VERSION 5.7 ;
  NOWIREEXTENSIONATPIN ON ;
  DIVIDERCHAR "/" ;
  BUSBITCHARS "[]" ;
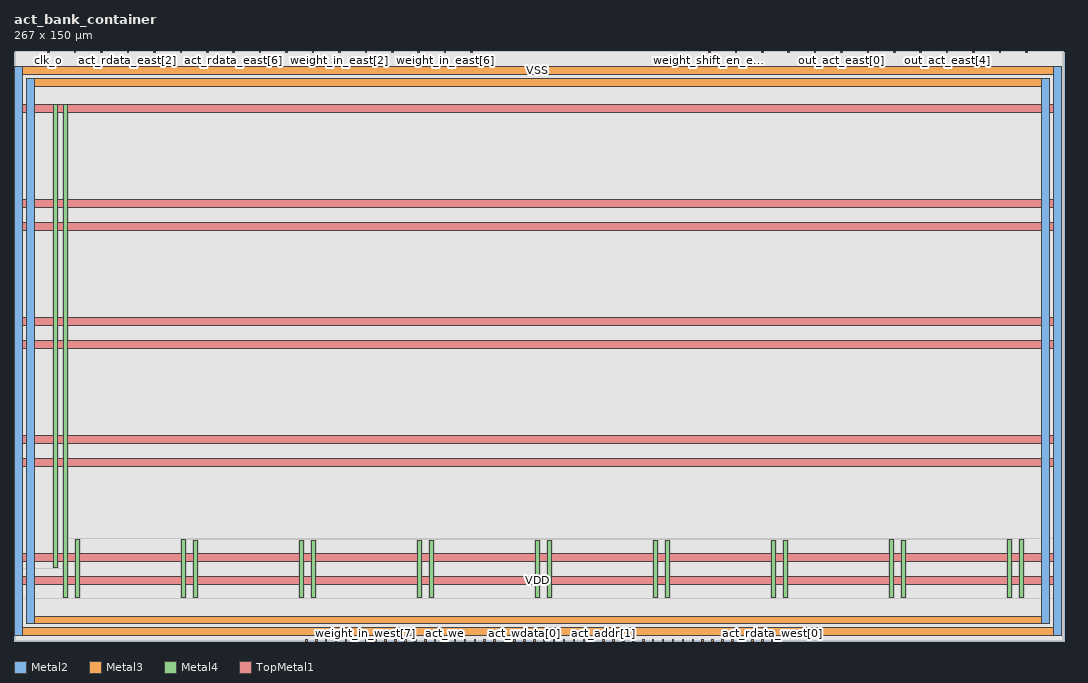
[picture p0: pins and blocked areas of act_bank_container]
MACRO act_bank_container
  CLASS BLOCK ;
  FOREIGN act_bank_container ;
  ORIGIN 0.000 0.000 ;
  SIZE 267.000 BY 150.000 ;
  PIN VDD
    DIRECTION INOUT ;
    USE POWER ;
    PORT
      LAYER Metal2 ;
        RECT 3.120 4.340 5.120 143.080 ;
    END
    PORT
      LAYER Metal2 ;
        RECT 261.280 4.340 263.280 143.080 ;
    END
    PORT
      LAYER Metal3 ;
        RECT 3.120 4.340 263.280 6.340 ;
    END
    PORT
      LAYER Metal3 ;
        RECT 3.120 141.080 263.280 143.080 ;
    END
    PORT
      LAYER Metal4 ;
        RECT 12.620 11.120 13.620 136.340 ;
    END
    PORT
      LAYER Metal4 ;
        RECT 42.620 11.120 43.620 25.760 ;
    END
    PORT
      LAYER Metal4 ;
        RECT 72.620 11.120 73.620 25.520 ;
    END
    PORT
      LAYER Metal4 ;
        RECT 102.620 11.120 103.620 25.520 ;
    END
    PORT
      LAYER Metal4 ;
        RECT 132.620 11.120 133.620 25.520 ;
    END
    PORT
      LAYER Metal4 ;
        RECT 162.620 11.120 163.620 25.520 ;
    END
    PORT
      LAYER Metal4 ;
        RECT 192.620 11.120 193.620 25.520 ;
    END
    PORT
      LAYER Metal4 ;
        RECT 222.620 11.120 223.620 25.760 ;
    END
    PORT
      LAYER Metal4 ;
        RECT 252.620 11.120 253.620 25.760 ;
    END
    PORT
      LAYER TopMetal1 ;
        RECT 0.120 14.340 266.280 16.340 ;
    END
    PORT
      LAYER TopMetal1 ;
        RECT 0.120 44.340 266.280 46.340 ;
    END
    PORT
      LAYER TopMetal1 ;
        RECT 0.120 74.340 266.280 76.340 ;
    END
    PORT
      LAYER TopMetal1 ;
        RECT 0.120 104.340 266.280 106.340 ;
    END
    PORT
      LAYER TopMetal1 ;
        RECT 0.120 134.340 266.280 136.340 ;
    END
  END VDD
  PIN VSS
    DIRECTION INOUT ;
    USE GROUND ;
    PORT
      LAYER Metal2 ;
        RECT 0.120 1.340 2.120 146.080 ;
    END
    PORT
      LAYER Metal2 ;
        RECT 264.280 1.340 266.280 146.080 ;
    END
    PORT
      LAYER Metal3 ;
        RECT 0.120 1.340 266.280 3.340 ;
    END
    PORT
      LAYER Metal3 ;
        RECT 0.120 144.080 266.280 146.080 ;
    END
    PORT
      LAYER Metal4 ;
        RECT 15.620 11.120 16.620 25.760 ;
    END
    PORT
      LAYER Metal4 ;
        RECT 45.620 11.120 46.620 25.520 ;
    END
    PORT
      LAYER Metal4 ;
        RECT 75.620 11.120 76.620 25.520 ;
    END
    PORT
      LAYER Metal4 ;
        RECT 105.620 11.120 106.620 25.520 ;
    END
    PORT
      LAYER Metal4 ;
        RECT 135.620 11.120 136.620 25.520 ;
    END
    PORT
      LAYER Metal4 ;
        RECT 165.620 11.120 166.620 25.520 ;
    END
    PORT
      LAYER Metal4 ;
        RECT 195.620 11.120 196.620 25.520 ;
    END
    PORT
      LAYER Metal4 ;
        RECT 225.620 11.120 226.620 25.520 ;
    END
    PORT
      LAYER Metal4 ;
        RECT 255.620 11.120 256.620 25.760 ;
    END
    PORT
      LAYER TopMetal1 ;
        RECT 0.120 20.340 266.280 22.340 ;
    END
    PORT
      LAYER TopMetal1 ;
        RECT 0.120 50.340 266.280 52.340 ;
    END
    PORT
      LAYER TopMetal1 ;
        RECT 0.120 80.340 266.280 82.340 ;
    END
    PORT
      LAYER TopMetal1 ;
        RECT 0.120 110.340 266.280 112.340 ;
    END
    PORT
      LAYER Metal4 ;
        RECT 10.060 18.680 11.060 136.300 ;
    END
  END VSS
  PIN act_addr[0]
    DIRECTION INPUT ;
    USE SIGNAL ;
    ANTENNAGATEAREA 0.180700 ;
    PORT
      LAYER Metal3 ;
        RECT 152.260 0.000 152.660 0.400 ;
    END
  END act_addr[0]
  PIN act_addr[1]
    DIRECTION INPUT ;
    USE SIGNAL ;
    ANTENNAGATEAREA 0.180700 ;
    PORT
      LAYER Metal3 ;
        RECT 149.740 0.000 150.140 0.400 ;
    END
  END act_addr[1]
  PIN act_addr[2]
    DIRECTION INPUT ;
    USE SIGNAL ;
    ANTENNAGATEAREA 0.180700 ;
    PORT
      LAYER Metal3 ;
        RECT 147.220 0.000 147.620 0.400 ;
    END
  END act_addr[2]
  PIN act_addr[3]
    DIRECTION INPUT ;
    USE SIGNAL ;
    ANTENNAGATEAREA 0.180700 ;
    PORT
      LAYER Metal3 ;
        RECT 144.700 0.000 145.100 0.400 ;
    END
  END act_addr[3]
  PIN act_addr[4]
    DIRECTION INPUT ;
    USE SIGNAL ;
    ANTENNAGATEAREA 0.180700 ;
    PORT
      LAYER Metal3 ;
        RECT 142.180 0.000 142.580 0.400 ;
    END
  END act_addr[4]
  PIN act_addr[5]
    DIRECTION INPUT ;
    USE SIGNAL ;
    ANTENNAGATEAREA 0.180700 ;
    PORT
      LAYER Metal3 ;
        RECT 139.660 0.000 140.060 0.400 ;
    END
  END act_addr[5]
  PIN act_addr[6]
    DIRECTION INPUT ;
    USE SIGNAL ;
    ANTENNAGATEAREA 0.180700 ;
    PORT
      LAYER Metal3 ;
        RECT 137.140 0.000 137.540 0.400 ;
    END
  END act_addr[6]
  PIN act_addr[7]
    DIRECTION INPUT ;
    USE SIGNAL ;
    ANTENNAGATEAREA 0.180700 ;
    PORT
      LAYER Metal3 ;
        RECT 134.620 0.000 135.020 0.400 ;
    END
  END act_addr[7]
  PIN act_addr[8]
    DIRECTION INPUT ;
    USE SIGNAL ;
    ANTENNAGATEAREA 0.180700 ;
    PORT
      LAYER Metal3 ;
        RECT 132.100 0.000 132.500 0.400 ;
    END
  END act_addr[8]
  PIN act_rdata_east[0]
    DIRECTION OUTPUT ;
    USE SIGNAL ;
    ANTENNADIFFAREA 0.708600 ;
    PORT
      LAYER Metal3 ;
        RECT 15.340 149.600 15.740 150.000 ;
    END
  END act_rdata_east[0]
  PIN act_rdata_east[1]
    DIRECTION OUTPUT ;
    USE SIGNAL ;
    ANTENNADIFFAREA 0.708600 ;
    PORT
      LAYER Metal3 ;
        RECT 22.060 149.600 22.460 150.000 ;
    END
  END act_rdata_east[1]
  PIN act_rdata_east[2]
    DIRECTION OUTPUT ;
    USE SIGNAL ;
    ANTENNADIFFAREA 0.708600 ;
    PORT
      LAYER Metal3 ;
        RECT 28.780 149.600 29.180 150.000 ;
    END
  END act_rdata_east[2]
  PIN act_rdata_east[3]
    DIRECTION OUTPUT ;
    USE SIGNAL ;
    ANTENNADIFFAREA 0.708600 ;
    PORT
      LAYER Metal3 ;
        RECT 35.500 149.600 35.900 150.000 ;
    END
  END act_rdata_east[3]
  PIN act_rdata_east[4]
    DIRECTION OUTPUT ;
    USE SIGNAL ;
    ANTENNADIFFAREA 0.708600 ;
    PORT
      LAYER Metal3 ;
        RECT 42.220 149.600 42.620 150.000 ;
    END
  END act_rdata_east[4]
  PIN act_rdata_east[5]
    DIRECTION OUTPUT ;
    USE SIGNAL ;
    ANTENNADIFFAREA 0.708600 ;
    PORT
      LAYER Metal3 ;
        RECT 48.940 149.600 49.340 150.000 ;
    END
  END act_rdata_east[5]
  PIN act_rdata_east[6]
    DIRECTION OUTPUT ;
    USE SIGNAL ;
    ANTENNADIFFAREA 0.708600 ;
    PORT
      LAYER Metal3 ;
        RECT 55.660 149.600 56.060 150.000 ;
    END
  END act_rdata_east[6]
  PIN act_rdata_east[7]
    DIRECTION OUTPUT ;
    USE SIGNAL ;
    ANTENNADIFFAREA 0.708600 ;
    PORT
      LAYER Metal3 ;
        RECT 62.380 149.600 62.780 150.000 ;
    END
  END act_rdata_east[7]
  PIN act_rdata_west[0]
    DIRECTION OUTPUT ;
    USE SIGNAL ;
    ANTENNADIFFAREA 0.708600 ;
    PORT
      LAYER Metal3 ;
        RECT 192.580 0.000 192.980 0.400 ;
    END
  END act_rdata_west[0]
  PIN act_rdata_west[1]
    DIRECTION OUTPUT ;
    USE SIGNAL ;
    ANTENNADIFFAREA 0.708600 ;
    PORT
      LAYER Metal3 ;
        RECT 190.060 0.000 190.460 0.400 ;
    END
  END act_rdata_west[1]
  PIN act_rdata_west[2]
    DIRECTION OUTPUT ;
    USE SIGNAL ;
    ANTENNADIFFAREA 0.708600 ;
    PORT
      LAYER Metal3 ;
        RECT 187.540 0.000 187.940 0.400 ;
    END
  END act_rdata_west[2]
  PIN act_rdata_west[3]
    DIRECTION OUTPUT ;
    USE SIGNAL ;
    ANTENNADIFFAREA 0.708600 ;
    PORT
      LAYER Metal3 ;
        RECT 185.020 0.000 185.420 0.400 ;
    END
  END act_rdata_west[3]
  PIN act_rdata_west[4]
    DIRECTION OUTPUT ;
    USE SIGNAL ;
    ANTENNADIFFAREA 0.708600 ;
    PORT
      LAYER Metal3 ;
        RECT 182.500 0.000 182.900 0.400 ;
    END
  END act_rdata_west[4]
  PIN act_rdata_west[5]
    DIRECTION OUTPUT ;
    USE SIGNAL ;
    ANTENNADIFFAREA 0.708600 ;
    PORT
      LAYER Metal3 ;
        RECT 179.980 0.000 180.380 0.400 ;
    END
  END act_rdata_west[5]
  PIN act_rdata_west[6]
    DIRECTION OUTPUT ;
    USE SIGNAL ;
    ANTENNADIFFAREA 0.708600 ;
    PORT
      LAYER Metal3 ;
        RECT 177.460 0.000 177.860 0.400 ;
    END
  END act_rdata_west[6]
  PIN act_rdata_west[7]
    DIRECTION OUTPUT ;
    USE SIGNAL ;
    ANTENNADIFFAREA 0.708600 ;
    PORT
      LAYER Metal3 ;
        RECT 174.940 0.000 175.340 0.400 ;
    END
  END act_rdata_west[7]
  PIN act_wdata[0]
    DIRECTION INPUT ;
    USE SIGNAL ;
    ANTENNAGATEAREA 0.180700 ;
    PORT
      LAYER Metal3 ;
        RECT 129.580 0.000 129.980 0.400 ;
    END
  END act_wdata[0]
  PIN act_wdata[1]
    DIRECTION INPUT ;
    USE SIGNAL ;
    ANTENNAGATEAREA 0.180700 ;
    PORT
      LAYER Metal3 ;
        RECT 127.060 0.000 127.460 0.400 ;
    END
  END act_wdata[1]
  PIN act_wdata[2]
    DIRECTION INPUT ;
    USE SIGNAL ;
    ANTENNAGATEAREA 0.180700 ;
    PORT
      LAYER Metal3 ;
        RECT 124.540 0.000 124.940 0.400 ;
    END
  END act_wdata[2]
  PIN act_wdata[3]
    DIRECTION INPUT ;
    USE SIGNAL ;
    ANTENNAGATEAREA 0.180700 ;
    PORT
      LAYER Metal3 ;
        RECT 122.020 0.000 122.420 0.400 ;
    END
  END act_wdata[3]
  PIN act_wdata[4]
    DIRECTION INPUT ;
    USE SIGNAL ;
    ANTENNAGATEAREA 0.180700 ;
    PORT
      LAYER Metal3 ;
        RECT 119.500 0.000 119.900 0.400 ;
    END
  END act_wdata[4]
  PIN act_wdata[5]
    DIRECTION INPUT ;
    USE SIGNAL ;
    ANTENNAGATEAREA 0.180700 ;
    PORT
      LAYER Metal3 ;
        RECT 116.980 0.000 117.380 0.400 ;
    END
  END act_wdata[5]
  PIN act_wdata[6]
    DIRECTION INPUT ;
    USE SIGNAL ;
    ANTENNAGATEAREA 0.180700 ;
    PORT
      LAYER Metal3 ;
        RECT 114.460 0.000 114.860 0.400 ;
    END
  END act_wdata[6]
  PIN act_wdata[7]
    DIRECTION INPUT ;
    USE SIGNAL ;
    ANTENNAGATEAREA 0.180700 ;
    PORT
      LAYER Metal3 ;
        RECT 111.940 0.000 112.340 0.400 ;
    END
  END act_wdata[7]
  PIN act_we
    DIRECTION INPUT ;
    USE SIGNAL ;
    ANTENNAGATEAREA 0.180700 ;
    PORT
      LAYER Metal3 ;
        RECT 109.420 0.000 109.820 0.400 ;
    END
  END act_we
  PIN clk_i
    DIRECTION INPUT ;
    USE SIGNAL ;
    ANTENNAGATEAREA 0.381550 ;
    PORT
      LAYER Metal3 ;
        RECT 74.140 0.000 74.540 0.400 ;
    END
  END clk_i
  PIN clk_o
    DIRECTION OUTPUT ;
    USE SIGNAL ;
    ANTENNADIFFAREA 0.708600 ;
    PORT
      LAYER Metal3 ;
        RECT 8.620 149.600 9.020 150.000 ;
    END
  END clk_o
  PIN out_act_east[0]
    DIRECTION INPUT ;
    USE SIGNAL ;
    ANTENNAGATEAREA 0.180700 ;
    PORT
      LAYER Metal3 ;
        RECT 210.220 149.600 210.620 150.000 ;
    END
  END out_act_east[0]
  PIN out_act_east[1]
    DIRECTION INPUT ;
    USE SIGNAL ;
    ANTENNAGATEAREA 0.180700 ;
    PORT
      LAYER Metal3 ;
        RECT 216.940 149.600 217.340 150.000 ;
    END
  END out_act_east[1]
  PIN out_act_east[2]
    DIRECTION INPUT ;
    USE SIGNAL ;
    ANTENNAGATEAREA 0.180700 ;
    ANTENNADIFFAREA 2.015400 ;
    PORT
      LAYER Metal3 ;
        RECT 223.660 149.600 224.060 150.000 ;
    END
  END out_act_east[2]
  PIN out_act_east[3]
    DIRECTION INPUT ;
    USE SIGNAL ;
    ANTENNAGATEAREA 0.180700 ;
    ANTENNADIFFAREA 2.015400 ;
    PORT
      LAYER Metal3 ;
        RECT 230.380 149.600 230.780 150.000 ;
    END
  END out_act_east[3]
  PIN out_act_east[4]
    DIRECTION INPUT ;
    USE SIGNAL ;
    ANTENNAGATEAREA 0.180700 ;
    PORT
      LAYER Metal3 ;
        RECT 237.100 149.600 237.500 150.000 ;
    END
  END out_act_east[4]
  PIN out_act_east[5]
    DIRECTION INPUT ;
    USE SIGNAL ;
    ANTENNAGATEAREA 0.180700 ;
    PORT
      LAYER Metal3 ;
        RECT 243.820 149.600 244.220 150.000 ;
    END
  END out_act_east[5]
  PIN out_act_east[6]
    DIRECTION INPUT ;
    USE SIGNAL ;
    ANTENNAGATEAREA 0.180700 ;
    PORT
      LAYER Metal3 ;
        RECT 250.540 149.600 250.940 150.000 ;
    END
  END out_act_east[6]
  PIN out_act_east[7]
    DIRECTION INPUT ;
    USE SIGNAL ;
    ANTENNAGATEAREA 0.180700 ;
    PORT
      LAYER Metal3 ;
        RECT 257.260 149.600 257.660 150.000 ;
    END
  END out_act_east[7]
  PIN out_act_west[0]
    DIRECTION OUTPUT ;
    USE SIGNAL ;
    ANTENNADIFFAREA 0.708600 ;
    PORT
      LAYER Metal3 ;
        RECT 172.420 0.000 172.820 0.400 ;
    END
  END out_act_west[0]
  PIN out_act_west[1]
    DIRECTION OUTPUT ;
    USE SIGNAL ;
    ANTENNADIFFAREA 0.708600 ;
    PORT
      LAYER Metal3 ;
        RECT 169.900 0.000 170.300 0.400 ;
    END
  END out_act_west[1]
  PIN out_act_west[2]
    DIRECTION OUTPUT ;
    USE SIGNAL ;
    ANTENNADIFFAREA 0.708600 ;
    PORT
      LAYER Metal3 ;
        RECT 167.380 0.000 167.780 0.400 ;
    END
  END out_act_west[2]
  PIN out_act_west[3]
    DIRECTION OUTPUT ;
    USE SIGNAL ;
    ANTENNADIFFAREA 0.708600 ;
    PORT
      LAYER Metal3 ;
        RECT 164.860 0.000 165.260 0.400 ;
    END
  END out_act_west[3]
  PIN out_act_west[4]
    DIRECTION OUTPUT ;
    USE SIGNAL ;
    ANTENNADIFFAREA 0.708600 ;
    PORT
      LAYER Metal3 ;
        RECT 162.340 0.000 162.740 0.400 ;
    END
  END out_act_west[4]
  PIN out_act_west[5]
    DIRECTION OUTPUT ;
    USE SIGNAL ;
    ANTENNADIFFAREA 0.708600 ;
    PORT
      LAYER Metal3 ;
        RECT 159.820 0.000 160.220 0.400 ;
    END
  END out_act_west[5]
  PIN out_act_west[6]
    DIRECTION OUTPUT ;
    USE SIGNAL ;
    ANTENNADIFFAREA 0.708600 ;
    PORT
      LAYER Metal3 ;
        RECT 157.300 0.000 157.700 0.400 ;
    END
  END out_act_west[6]
  PIN out_act_west[7]
    DIRECTION OUTPUT ;
    USE SIGNAL ;
    ANTENNADIFFAREA 0.708600 ;
    PORT
      LAYER Metal3 ;
        RECT 154.780 0.000 155.180 0.400 ;
    END
  END out_act_west[7]
  PIN weight_in_east[0]
    DIRECTION OUTPUT ;
    USE SIGNAL ;
    ANTENNADIFFAREA 0.708600 ;
    PORT
      LAYER Metal3 ;
        RECT 69.100 149.600 69.500 150.000 ;
    END
  END weight_in_east[0]
  PIN weight_in_east[1]
    DIRECTION OUTPUT ;
    USE SIGNAL ;
    ANTENNADIFFAREA 0.708600 ;
    PORT
      LAYER Metal3 ;
        RECT 75.820 149.600 76.220 150.000 ;
    END
  END weight_in_east[1]
  PIN weight_in_east[2]
    DIRECTION OUTPUT ;
    USE SIGNAL ;
    ANTENNADIFFAREA 0.708600 ;
    PORT
      LAYER Metal3 ;
        RECT 82.540 149.600 82.940 150.000 ;
    END
  END weight_in_east[2]
  PIN weight_in_east[3]
    DIRECTION OUTPUT ;
    USE SIGNAL ;
    ANTENNADIFFAREA 0.708600 ;
    PORT
      LAYER Metal3 ;
        RECT 89.260 149.600 89.660 150.000 ;
    END
  END weight_in_east[3]
  PIN weight_in_east[4]
    DIRECTION OUTPUT ;
    USE SIGNAL ;
    ANTENNADIFFAREA 0.708600 ;
    PORT
      LAYER Metal3 ;
        RECT 95.980 149.600 96.380 150.000 ;
    END
  END weight_in_east[4]
  PIN weight_in_east[5]
    DIRECTION OUTPUT ;
    USE SIGNAL ;
    ANTENNADIFFAREA 0.708600 ;
    PORT
      LAYER Metal3 ;
        RECT 102.700 149.600 103.100 150.000 ;
    END
  END weight_in_east[5]
  PIN weight_in_east[6]
    DIRECTION OUTPUT ;
    USE SIGNAL ;
    ANTENNADIFFAREA 0.708600 ;
    PORT
      LAYER Metal3 ;
        RECT 109.420 149.600 109.820 150.000 ;
    END
  END weight_in_east[6]
  PIN weight_in_east[7]
    DIRECTION OUTPUT ;
    USE SIGNAL ;
    ANTENNADIFFAREA 0.708600 ;
    PORT
      LAYER Metal3 ;
        RECT 116.140 149.600 116.540 150.000 ;
    END
  END weight_in_east[7]
  PIN weight_in_west[0]
    DIRECTION INPUT ;
    USE SIGNAL ;
    ANTENNAGATEAREA 0.180700 ;
    PORT
      LAYER Metal3 ;
        RECT 106.900 0.000 107.300 0.400 ;
    END
  END weight_in_west[0]
  PIN weight_in_west[1]
    DIRECTION INPUT ;
    USE SIGNAL ;
    ANTENNAGATEAREA 0.180700 ;
    PORT
      LAYER Metal3 ;
        RECT 104.380 0.000 104.780 0.400 ;
    END
  END weight_in_west[1]
  PIN weight_in_west[2]
    DIRECTION INPUT ;
    USE SIGNAL ;
    ANTENNAGATEAREA 0.180700 ;
    PORT
      LAYER Metal3 ;
        RECT 101.860 0.000 102.260 0.400 ;
    END
  END weight_in_west[2]
  PIN weight_in_west[3]
    DIRECTION INPUT ;
    USE SIGNAL ;
    ANTENNAGATEAREA 0.180700 ;
    PORT
      LAYER Metal3 ;
        RECT 99.340 0.000 99.740 0.400 ;
    END
  END weight_in_west[3]
  PIN weight_in_west[4]
    DIRECTION INPUT ;
    USE SIGNAL ;
    ANTENNAGATEAREA 0.180700 ;
    PORT
      LAYER Metal3 ;
        RECT 96.820 0.000 97.220 0.400 ;
    END
  END weight_in_west[4]
  PIN weight_in_west[5]
    DIRECTION INPUT ;
    USE SIGNAL ;
    ANTENNAGATEAREA 0.180700 ;
    PORT
      LAYER Metal3 ;
        RECT 94.300 0.000 94.700 0.400 ;
    END
  END weight_in_west[5]
  PIN weight_in_west[6]
    DIRECTION INPUT ;
    USE SIGNAL ;
    ANTENNAGATEAREA 0.180700 ;
    PORT
      LAYER Metal3 ;
        RECT 91.780 0.000 92.180 0.400 ;
    END
  END weight_in_west[6]
  PIN weight_in_west[7]
    DIRECTION INPUT ;
    USE SIGNAL ;
    ANTENNAGATEAREA 0.180700 ;
    PORT
      LAYER Metal3 ;
        RECT 89.260 0.000 89.660 0.400 ;
    END
  END weight_in_west[7]
  PIN weight_shift_en_east
    DIRECTION OUTPUT ;
    USE SIGNAL ;
    ANTENNADIFFAREA 0.708600 ;
    PORT
      LAYER Metal3 ;
        RECT 176.620 149.600 177.020 150.000 ;
    END
  END weight_shift_en_east
  PIN weight_shift_en_west
    DIRECTION INPUT ;
    USE SIGNAL ;
    ANTENNAGATEAREA 0.180700 ;
    PORT
      LAYER Metal3 ;
        RECT 86.740 0.000 87.140 0.400 ;
    END
  END weight_shift_en_west
  PIN xbar_sel_east[0]
    DIRECTION OUTPUT ;
    USE SIGNAL ;
    ANTENNADIFFAREA 0.708600 ;
    PORT
      LAYER Metal3 ;
        RECT 183.340 149.600 183.740 150.000 ;
    END
  END xbar_sel_east[0]
  PIN xbar_sel_east[1]
    DIRECTION OUTPUT ;
    USE SIGNAL ;
    ANTENNADIFFAREA 0.708600 ;
    PORT
      LAYER Metal3 ;
        RECT 190.060 149.600 190.460 150.000 ;
    END
  END xbar_sel_east[1]
  PIN xbar_sel_east[2]
    DIRECTION OUTPUT ;
    USE SIGNAL ;
    ANTENNADIFFAREA 0.708600 ;
    PORT
      LAYER Metal3 ;
        RECT 196.780 149.600 197.180 150.000 ;
    END
  END xbar_sel_east[2]
  PIN xbar_sel_east[3]
    DIRECTION OUTPUT ;
    USE SIGNAL ;
    ANTENNADIFFAREA 0.708600 ;
    PORT
      LAYER Metal3 ;
        RECT 203.500 149.600 203.900 150.000 ;
    END
  END xbar_sel_east[3]
  PIN xbar_sel_west[0]
    DIRECTION INPUT ;
    USE SIGNAL ;
    ANTENNAGATEAREA 0.180700 ;
    PORT
      LAYER Metal3 ;
        RECT 84.220 0.000 84.620 0.400 ;
    END
  END xbar_sel_west[0]
  PIN xbar_sel_west[1]
    DIRECTION INPUT ;
    USE SIGNAL ;
    ANTENNAGATEAREA 0.180700 ;
    PORT
      LAYER Metal3 ;
        RECT 81.700 0.000 82.100 0.400 ;
    END
  END xbar_sel_west[1]
  PIN xbar_sel_west[2]
    DIRECTION INPUT ;
    USE SIGNAL ;
    ANTENNAGATEAREA 0.180700 ;
    PORT
      LAYER Metal3 ;
        RECT 79.180 0.000 79.580 0.400 ;
    END
  END xbar_sel_west[2]
  PIN xbar_sel_west[3]
    DIRECTION INPUT ;
    USE SIGNAL ;
    ANTENNAGATEAREA 0.180700 ;
    PORT
      LAYER Metal3 ;
        RECT 76.660 0.000 77.060 0.400 ;
    END
  END xbar_sel_west[3]
  OBS
      LAYER GatPoly ;
        RECT 9.120 11.190 257.280 138.140 ;
      LAYER Metal1 ;
        RECT 9.120 11.120 257.280 138.095 ;
      LAYER Metal2 ;
        RECT 5.655 146.290 266.980 149.945 ;
        RECT 5.655 143.290 264.070 146.290 ;
        RECT 5.655 4.130 261.070 143.290 ;
        RECT 263.490 4.130 264.070 143.290 ;
        RECT 5.655 1.130 264.070 4.130 ;
        RECT 266.490 1.130 266.980 146.290 ;
        RECT 5.655 0.055 266.980 1.130 ;
      LAYER Metal3 ;
        RECT 0.255 149.390 8.410 149.905 ;
        RECT 9.230 149.390 15.130 149.905 ;
        RECT 15.950 149.390 21.850 149.905 ;
        RECT 22.670 149.390 28.570 149.905 ;
        RECT 29.390 149.390 35.290 149.905 ;
        RECT 36.110 149.390 42.010 149.905 ;
        RECT 42.830 149.390 48.730 149.905 ;
        RECT 49.550 149.390 55.450 149.905 ;
        RECT 56.270 149.390 62.170 149.905 ;
        RECT 62.990 149.390 68.890 149.905 ;
        RECT 69.710 149.390 75.610 149.905 ;
        RECT 76.430 149.390 82.330 149.905 ;
        RECT 83.150 149.390 89.050 149.905 ;
        RECT 89.870 149.390 95.770 149.905 ;
        RECT 96.590 149.390 102.490 149.905 ;
        RECT 103.310 149.390 109.210 149.905 ;
        RECT 110.030 149.390 115.930 149.905 ;
        RECT 116.750 149.390 176.410 149.905 ;
        RECT 177.230 149.390 183.130 149.905 ;
        RECT 183.950 149.390 189.850 149.905 ;
        RECT 190.670 149.390 196.570 149.905 ;
        RECT 197.390 149.390 203.290 149.905 ;
        RECT 204.110 149.390 210.010 149.905 ;
        RECT 210.830 149.390 216.730 149.905 ;
        RECT 217.550 149.390 223.450 149.905 ;
        RECT 224.270 149.390 230.170 149.905 ;
        RECT 230.990 149.390 236.890 149.905 ;
        RECT 237.710 149.390 243.610 149.905 ;
        RECT 244.430 149.390 250.330 149.905 ;
        RECT 251.150 149.390 257.050 149.905 ;
        RECT 257.870 149.390 266.545 149.905 ;
        RECT 0.255 146.290 266.545 149.390 ;
        RECT 266.490 143.870 266.545 146.290 ;
        RECT 0.255 143.290 266.545 143.870 ;
        RECT 0.255 140.870 2.910 143.290 ;
        RECT 263.490 140.870 266.545 143.290 ;
        RECT 0.255 6.550 266.545 140.870 ;
        RECT 0.255 4.130 2.910 6.550 ;
        RECT 263.490 4.130 266.545 6.550 ;
        RECT 0.255 3.550 266.545 4.130 ;
        RECT 266.490 1.130 266.545 3.550 ;
        RECT 0.255 0.610 266.545 1.130 ;
        RECT 0.255 0.095 73.930 0.610 ;
        RECT 74.750 0.095 76.450 0.610 ;
        RECT 77.270 0.095 78.970 0.610 ;
        RECT 79.790 0.095 81.490 0.610 ;
        RECT 82.310 0.095 84.010 0.610 ;
        RECT 84.830 0.095 86.530 0.610 ;
        RECT 87.350 0.095 89.050 0.610 ;
        RECT 89.870 0.095 91.570 0.610 ;
        RECT 92.390 0.095 94.090 0.610 ;
        RECT 94.910 0.095 96.610 0.610 ;
        RECT 97.430 0.095 99.130 0.610 ;
        RECT 99.950 0.095 101.650 0.610 ;
        RECT 102.470 0.095 104.170 0.610 ;
        RECT 104.990 0.095 106.690 0.610 ;
        RECT 107.510 0.095 109.210 0.610 ;
        RECT 110.030 0.095 111.730 0.610 ;
        RECT 112.550 0.095 114.250 0.610 ;
        RECT 115.070 0.095 116.770 0.610 ;
        RECT 117.590 0.095 119.290 0.610 ;
        RECT 120.110 0.095 121.810 0.610 ;
        RECT 122.630 0.095 124.330 0.610 ;
        RECT 125.150 0.095 126.850 0.610 ;
        RECT 127.670 0.095 129.370 0.610 ;
        RECT 130.190 0.095 131.890 0.610 ;
        RECT 132.710 0.095 134.410 0.610 ;
        RECT 135.230 0.095 136.930 0.610 ;
        RECT 137.750 0.095 139.450 0.610 ;
        RECT 140.270 0.095 141.970 0.610 ;
        RECT 142.790 0.095 144.490 0.610 ;
        RECT 145.310 0.095 147.010 0.610 ;
        RECT 147.830 0.095 149.530 0.610 ;
        RECT 150.350 0.095 152.050 0.610 ;
        RECT 152.870 0.095 154.570 0.610 ;
        RECT 155.390 0.095 157.090 0.610 ;
        RECT 157.910 0.095 159.610 0.610 ;
        RECT 160.430 0.095 162.130 0.610 ;
        RECT 162.950 0.095 164.650 0.610 ;
        RECT 165.470 0.095 167.170 0.610 ;
        RECT 167.990 0.095 169.690 0.610 ;
        RECT 170.510 0.095 172.210 0.610 ;
        RECT 173.030 0.095 174.730 0.610 ;
        RECT 175.550 0.095 177.250 0.610 ;
        RECT 178.070 0.095 179.770 0.610 ;
        RECT 180.590 0.095 182.290 0.610 ;
        RECT 183.110 0.095 184.810 0.610 ;
        RECT 185.630 0.095 187.330 0.610 ;
        RECT 188.150 0.095 189.850 0.610 ;
        RECT 190.670 0.095 192.370 0.610 ;
        RECT 193.190 0.095 266.545 0.610 ;
      LAYER Metal4 ;
        RECT 0.300 136.550 266.500 149.945 ;
        RECT 0.300 136.510 12.410 136.550 ;
        RECT 0.300 18.470 9.850 136.510 ;
        RECT 11.270 18.470 12.410 136.510 ;
        RECT 0.300 10.910 12.410 18.470 ;
        RECT 13.830 25.970 266.500 136.550 ;
        RECT 13.830 10.910 15.410 25.970 ;
        RECT 16.830 10.910 42.410 25.970 ;
        RECT 43.830 25.730 222.410 25.970 ;
        RECT 43.830 10.910 45.410 25.730 ;
        RECT 46.830 10.910 72.410 25.730 ;
        RECT 73.830 10.910 75.410 25.730 ;
        RECT 76.830 10.910 102.410 25.730 ;
        RECT 103.830 10.910 105.410 25.730 ;
        RECT 106.830 10.910 132.410 25.730 ;
        RECT 133.830 10.910 135.410 25.730 ;
        RECT 136.830 10.910 162.410 25.730 ;
        RECT 163.830 10.910 165.410 25.730 ;
        RECT 166.830 10.910 192.410 25.730 ;
        RECT 193.830 10.910 195.410 25.730 ;
        RECT 196.830 10.910 222.410 25.730 ;
        RECT 223.830 25.730 252.410 25.970 ;
        RECT 223.830 10.910 225.410 25.730 ;
        RECT 226.830 10.910 252.410 25.730 ;
        RECT 253.830 10.910 255.410 25.970 ;
        RECT 256.830 10.910 266.500 25.970 ;
        RECT 0.300 0.055 266.500 10.910 ;
  END
END act_bank_container
END LIBRARY

